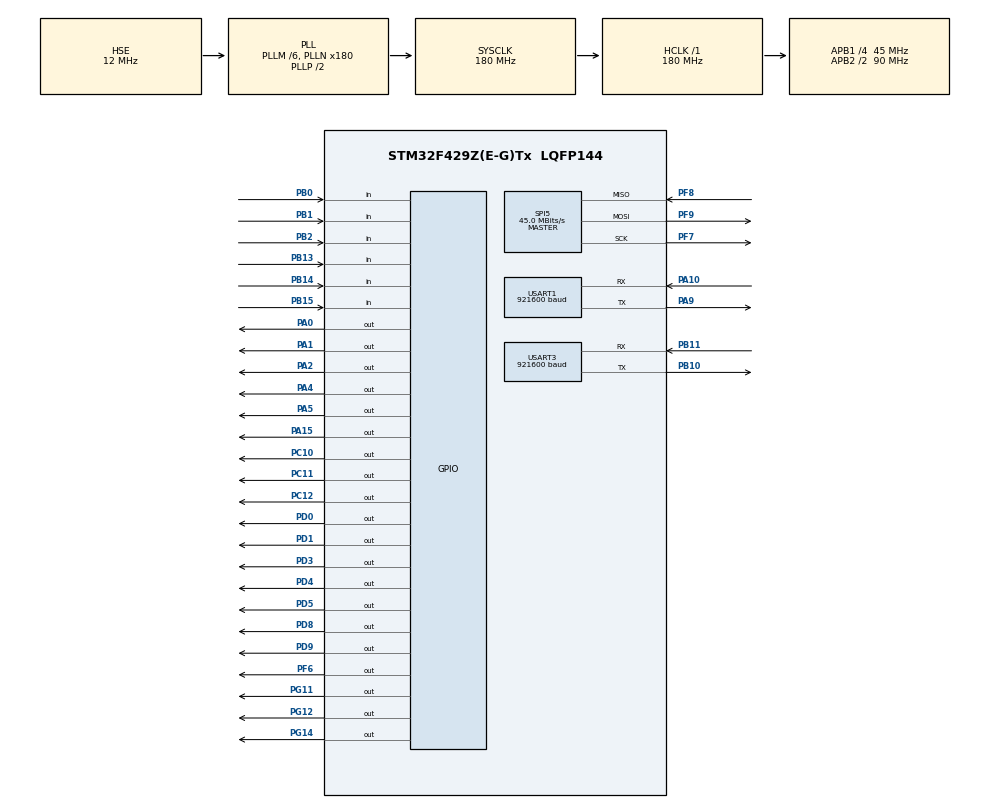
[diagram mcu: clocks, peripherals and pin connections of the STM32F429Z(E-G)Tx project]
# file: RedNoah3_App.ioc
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Dma.Request0=USART1_TX
Dma.Request1=USART1_RX
Dma.USART1_RX.1.Direction=DMA_PERIPH_TO_MEMORY
Dma.USART1_RX.1.FIFOMode=DMA_FIFOMODE_DISABLE
Dma.USART1_RX.1.Instance=DMA2_Stream2
Dma.USART1_RX.1.MemDataAlignment=DMA_MDATAALIGN_BYTE
Dma.USART1_RX.1.MemInc=DMA_MINC_ENABLE
Dma.USART1_RX.1.Mode=DMA_NORMAL
Dma.USART1_RX.1.PeriphDataAlignment=DMA_PDATAALIGN_BYTE
Dma.USART1_RX.1.PeriphInc=DMA_PINC_DISABLE
Dma.USART1_RX.1.Priority=DMA_PRIORITY_HIGH
Dma.USART1_TX.0.Direction=DMA_MEMORY_TO_PERIPH
Dma.USART1_TX.0.FIFOMode=DMA_FIFOMODE_DISABLE
Dma.USART1_TX.0.Instance=DMA2_Stream7
Dma.USART1_TX.0.MemDataAlignment=DMA_MDATAALIGN_BYTE
Dma.USART1_TX.0.MemInc=DMA_MINC_ENABLE
Dma.USART1_TX.0.Mode=DMA_NORMAL
Dma.USART1_TX.0.PeriphDataAlignment=DMA_PDATAALIGN_BYTE
Dma.USART1_TX.0.PeriphInc=DMA_PINC_DISABLE
Dma.USART1_TX.0.Priority=DMA_PRIORITY_HIGH
Mcu.Family=STM32F4
Mcu.Name=STM32F429Z(E-G)Tx
Mcu.Package=LQFP144
NVIC.DMA2_Stream2_IRQn=true\:0\:0\:false\:false\:true\:false\:true\:true
NVIC.DMA2_Stream7_IRQn=true\:0\:0\:false\:false\:true\:false\:true\:true
NVIC.PriorityGroup=NVIC_PRIORITYGROUP_4
NVIC.SPI5_IRQn=true\:0\:0\:false\:false\:true\:true\:true\:true
NVIC.TIM1_UP_TIM10_IRQn=true\:0\:0\:false\:false\:true\:true\:true\:true
NVIC.TIM7_IRQn=true\:10\:0\:true\:false\:true\:true\:true\:true
NVIC.USART1_IRQn=true\:0\:0\:false\:false\:true\:true\:true\:true
NVIC.USART3_IRQn=true\:0\:0\:false\:false\:true\:true\:true\:true
PA0/WKUP.Signal=GPIO_Output
PA1.Signal=GPIO_Output
PA10.Mode=Asynchronous
PA10.Signal=USART1_RX
PA13.Mode=Serial_Wire
PA13.Signal=SYS_JTMS-SWDIO
PA14.Mode=Serial_Wire
PA14.Signal=SYS_JTCK-SWCLK
PA15.Signal=GPIO_Output
PA2.Signal=GPIO_Output
PA4.Signal=GPIO_Output
PA5.Signal=GPIO_Output
PA9.Mode=Asynchronous
PA9.Signal=USART1_TX
PB0.Signal=GPIO_Input
PB1.Signal=GPIO_Input
PB10.Mode=Asynchronous
PB10.Signal=USART3_TX
PB11.Mode=Asynchronous
PB11.Signal=USART3_RX
PB13.Signal=GPIO_Input
PB14.Signal=GPIO_Input
PB15.Signal=GPIO_Input
PB2/BOOT1.Signal=GPIO_Input
PC10.Signal=GPIO_Output
PC11.Signal=GPIO_Output
PC12.Signal=GPIO_Output
PD0.Signal=GPIO_Output
PD1.Signal=GPIO_Output
PD3.Signal=GPIO_Output
PD4.Signal=GPIO_Output
PD5.Signal=GPIO_Output
PD8.Signal=GPIO_Output
PD9.Signal=GPIO_Output
PF6.Signal=GPIO_Output
PF7.Mode=Full_Duplex_Master
PF7.Signal=SPI5_SCK
PF8.Mode=Full_Duplex_Master
PF8.Signal=SPI5_MISO
PF9.Mode=Full_Duplex_Master
PF9.Signal=SPI5_MOSI
PG11.Signal=GPIO_Output
PG12.Signal=GPIO_Output
PG14.Signal=GPIO_Output
PH0/OSC_IN.Mode=HSE-External-Oscillator
PH0/OSC_IN.Signal=RCC_OSC_IN
PH1/OSC_OUT.Mode=HSE-External-Oscillator
PH1/OSC_OUT.Signal=RCC_OSC_OUT
ProjectManager.HeapSize=0x200
ProjectManager.StackSize=0x400
ProjectManager.TargetToolchain=MDK-ARM V5.32
RCC.48MHZClocksFreq_Value=90000000
RCC.AHBFreq_Value=180000000
RCC.APB1CLKDivider=RCC_HCLK_DIV4
RCC.APB1Freq_Value=45000000
RCC.APB1TimFreq_Value=90000000
RCC.APB2CLKDivider=RCC_HCLK_DIV2
RCC.APB2Freq_Value=90000000
RCC.APB2TimFreq_Value=180000000
RCC.CortexFreq_Value=180000000
RCC.HCLKFreq_Value=180000000
RCC.HSE_VALUE=12000000
RCC.HSI_VALUE=16000000
RCC.LSE_VALUE=32768
RCC.PLLM=6
RCC.PLLN=180
RCC.PLLSourceVirtual=RCC_PLLSOURCE_HSE
RCC.SYSCLKFreq_VALUE=180000000
RCC.SYSCLKSource=RCC_SYSCLKSOURCE_PLLCLK
RCC.VCOOutputFreq_Value=360000000
SPI5.BaudRatePrescaler=SPI_BAUDRATEPRESCALER_2
SPI5.CalculateBaudRate=45.0 MBits/s
SPI5.Direction=SPI_DIRECTION_2LINES
SPI5.Mode=SPI_MODE_MASTER
SPI5.VirtualType=VM_MASTER
USART1.BaudRate=921600
USART1.VirtualMode=VM_ASYNC
USART3.BaudRate=921600
USART3.VirtualMode=VM_ASYNC
VP_TIM10_VS_ClockSourceINT.Mode=Enable_Timer
VP_TIM7_VS_ClockSourceINT.Mode=Enable_Timer
board=custom

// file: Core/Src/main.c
/* USER CODE BEGIN Header */
/**
 ******************************************************************************
 * @file           : main.c
 * @brief          : Main program body
 ******************************************************************************
 * @attention
 *
 * Copyright (c) 2023 STMicroelectronics.
 * All rights reserved.
 *
 * This software is licensed under terms that can be found in the LICENSE file
 * in the root directory of this software component.
 * If no LICENSE file comes with this software, it is provided AS-IS.
 *
 ******************************************************************************
 */
/* USER CODE END Header */
#include "main.h"

SPI_HandleTypeDef hspi5;

TIM_HandleTypeDef htim7;
TIM_HandleTypeDef htim10;

UART_HandleTypeDef huart1;
UART_HandleTypeDef huart3;
DMA_HandleTypeDef hdma_usart1_tx;
DMA_HandleTypeDef hdma_usart1_rx;

void SystemClock_Config(void);
static void MX_GPIO_Init(void);
static void MX_DMA_Init(void);
static void MX_SPI5_Init(void);
static void MX_TIM7_Init(void);
static void MX_TIM10_Init(void);
static void MX_USART1_UART_Init(void);
static void MX_USART3_UART_Init(void);

int main(void)
{

  /* MCU Configuration--------------------------------------------------------*/

  /* Reset of all peripherals, Initializes the Flash interface and the Systick. */
  HAL_Init();

  /* Configure the system clock */
  SystemClock_Config();

  /* Initialize all configured peripherals */
  MX_GPIO_Init();
  MX_DMA_Init();
  MX_SPI5_Init();
  MX_TIM7_Init();
  MX_TIM10_Init();
  MX_USART1_UART_Init();
  MX_USART3_UART_Init();
  /* USER CODE BEGIN 2 */
  init_redhoah3_system();

  /* USER CODE END 2 */

  /* Infinite loop */
  /* USER CODE BEGIN WHILE */
  while (1)
  {
    rednoah3_main_task();
    /* USER CODE END WHILE */

  }
}

void SystemClock_Config(void)
{
  RCC_OscInitTypeDef RCC_OscInitStruct = {0};
  RCC_ClkInitTypeDef RCC_ClkInitStruct = {0};

  /** Configure the main internal regulator output voltage
  */
  __HAL_RCC_PWR_CLK_ENABLE();
  __HAL_PWR_VOLTAGESCALING_CONFIG(PWR_REGULATOR_VOLTAGE_SCALE1);

  /** Initializes the RCC Oscillators according to the specified parameters
  * in the RCC_OscInitTypeDef structure.
  */
  RCC_OscInitStruct.OscillatorType = RCC_OSCILLATORTYPE_HSE;
  RCC_OscInitStruct.HSEState = RCC_HSE_ON;
  RCC_OscInitStruct.PLL.PLLState = RCC_PLL_ON;
  RCC_OscInitStruct.PLL.PLLSource = RCC_PLLSOURCE_HSE;
  RCC_OscInitStruct.PLL.PLLM = 6;
  RCC_OscInitStruct.PLL.PLLN = 180;
  RCC_OscInitStruct.PLL.PLLP = RCC_PLLP_DIV2;
  RCC_OscInitStruct.PLL.PLLQ = 4;
  if (HAL_RCC_OscConfig(&RCC_OscInitStruct) != HAL_OK)
  {
    Error_Handler();
  }

  /** Activate the Over-Drive mode
  */
  if (HAL_PWREx_EnableOverDrive() != HAL_OK)
  {
    Error_Handler();
  }

  /** Initializes the CPU, AHB and APB buses clocks
  */
  RCC_ClkInitStruct.ClockType = RCC_CLOCKTYPE_HCLK|RCC_CLOCKTYPE_SYSCLK
                              |RCC_CLOCKTYPE_PCLK1|RCC_CLOCKTYPE_PCLK2;
  RCC_ClkInitStruct.SYSCLKSource = RCC_SYSCLKSOURCE_PLLCLK;
  RCC_ClkInitStruct.AHBCLKDivider = RCC_SYSCLK_DIV1;
  RCC_ClkInitStruct.APB1CLKDivider = RCC_HCLK_DIV4;
  RCC_ClkInitStruct.APB2CLKDivider = RCC_HCLK_DIV2;

  if (HAL_RCC_ClockConfig(&RCC_ClkInitStruct, FLASH_LATENCY_5) != HAL_OK)
  {
    Error_Handler();
  }
}

static void MX_SPI5_Init(void)
{

  /* SPI5 parameter configuration*/
  hspi5.Instance = SPI5;
  hspi5.Init.Mode = SPI_MODE_MASTER;
  hspi5.Init.Direction = SPI_DIRECTION_2LINES;
  hspi5.Init.DataSize = SPI_DATASIZE_8BIT;
  hspi5.Init.CLKPolarity = SPI_POLARITY_LOW;
  hspi5.Init.CLKPhase = SPI_PHASE_1EDGE;
  hspi5.Init.NSS = SPI_NSS_SOFT;
  hspi5.Init.BaudRatePrescaler = SPI_BAUDRATEPRESCALER_2;
  hspi5.Init.FirstBit = SPI_FIRSTBIT_MSB;
  hspi5.Init.TIMode = SPI_TIMODE_DISABLE;
  hspi5.Init.CRCCalculation = SPI_CRCCALCULATION_DISABLE;
  hspi5.Init.CRCPolynomial = 10;
  if (HAL_SPI_Init(&hspi5) != HAL_OK)
  {
    Error_Handler();
  }
  /* USER CODE BEGIN SPI5_Init 2 */
	hspi5.Init.BaudRatePrescaler = SPI_BAUDRATEPRESCALER_128;
	hspi5.Init.CLKPolarity = SPI_POLARITY_LOW;
  hspi5.Init.CLKPhase = SPI_PHASE_2EDGE;
	HAL_GPIO_WritePin(GPIOF, GPIO_PIN_6, 1);

	 if (HAL_SPI_Init(&hspi5) != HAL_OK)
  {
    Error_Handler();
  }

  /* USER CODE END SPI5_Init 2 */

}

static void MX_TIM7_Init(void)
{

  TIM_MasterConfigTypeDef sMasterConfig = {0};

  htim7.Instance = TIM7;
  htim7.Init.Prescaler = 0;
  htim7.Init.CounterMode = TIM_COUNTERMODE_UP;
  htim7.Init.Period = 65535;
  htim7.Init.AutoReloadPreload = TIM_AUTORELOAD_PRELOAD_DISABLE;
  if (HAL_TIM_Base_Init(&htim7) != HAL_OK)
  {
    Error_Handler();
  }
  sMasterConfig.MasterOutputTrigger = TIM_TRGO_RESET;
  sMasterConfig.MasterSlaveMode = TIM_MASTERSLAVEMODE_DISABLE;
  if (HAL_TIMEx_MasterConfigSynchronization(&htim7, &sMasterConfig) != HAL_OK)
  {
    Error_Handler();
  }

}

static void MX_TIM10_Init(void)
{

  htim10.Instance = TIM10;
  htim10.Init.Prescaler = 0;
  htim10.Init.CounterMode = TIM_COUNTERMODE_UP;
  htim10.Init.Period = 65535;
  htim10.Init.ClockDivision = TIM_CLOCKDIVISION_DIV1;
  htim10.Init.AutoReloadPreload = TIM_AUTORELOAD_PRELOAD_DISABLE;
  if (HAL_TIM_Base_Init(&htim10) != HAL_OK)
  {
    Error_Handler();
  }

}

static void MX_USART1_UART_Init(void)
{

  huart1.Instance = USART1;
  huart1.Init.BaudRate = 921600;
  huart1.Init.WordLength = UART_WORDLENGTH_8B;
  huart1.Init.StopBits = UART_STOPBITS_1;
  huart1.Init.Parity = UART_PARITY_NONE;
  huart1.Init.Mode = UART_MODE_TX_RX;
  huart1.Init.HwFlowCtl = UART_HWCONTROL_NONE;
  huart1.Init.OverSampling = UART_OVERSAMPLING_16;
  if (HAL_UART_Init(&huart1) != HAL_OK)
  {
    Error_Handler();
  }

}

static void MX_USART3_UART_Init(void)
{

  huart3.Instance = USART3;
  huart3.Init.BaudRate = 921600;
  huart3.Init.WordLength = UART_WORDLENGTH_8B;
  huart3.Init.StopBits = UART_STOPBITS_1;
  huart3.Init.Parity = UART_PARITY_NONE;
  huart3.Init.Mode = UART_MODE_TX_RX;
  huart3.Init.HwFlowCtl = UART_HWCONTROL_NONE;
  huart3.Init.OverSampling = UART_OVERSAMPLING_16;
  if (HAL_UART_Init(&huart3) != HAL_OK)
  {
    Error_Handler();
  }

}

static void MX_DMA_Init(void)
{

  /* DMA controller clock enable */
  __HAL_RCC_DMA2_CLK_ENABLE();

  /* DMA interrupt init */
  /* DMA2_Stream2_IRQn interrupt configuration */
  HAL_NVIC_SetPriority(DMA2_Stream2_IRQn, 0, 0);
  HAL_NVIC_EnableIRQ(DMA2_Stream2_IRQn);
  /* DMA2_Stream7_IRQn interrupt configuration */
  HAL_NVIC_SetPriority(DMA2_Stream7_IRQn, 0, 0);
  HAL_NVIC_EnableIRQ(DMA2_Stream7_IRQn);

}

static void MX_GPIO_Init(void)
{
  GPIO_InitTypeDef GPIO_InitStruct = {0};

  /* GPIO Ports Clock Enable */
  __HAL_RCC_GPIOE_CLK_ENABLE();
  __HAL_RCC_GPIOF_CLK_ENABLE();
  __HAL_RCC_GPIOH_CLK_ENABLE();
  __HAL_RCC_GPIOA_CLK_ENABLE();
  __HAL_RCC_GPIOB_CLK_ENABLE();
  __HAL_RCC_GPIOD_CLK_ENABLE();
  __HAL_RCC_GPIOC_CLK_ENABLE();
  __HAL_RCC_GPIOG_CLK_ENABLE();

  /*Configure GPIO pin Output Level */
  HAL_GPIO_WritePin(GPIOE, GPIO_PIN_3|GPIO_PIN_4, GPIO_PIN_RESET);

  /*Configure GPIO pin Output Level */
  HAL_GPIO_WritePin(GPIOF, GPIO_PIN_6, GPIO_PIN_RESET);

  /*Configure GPIO pin Output Level */
  HAL_GPIO_WritePin(GPIOA, GPIO_PIN_0|GPIO_PIN_1|GPIO_PIN_2|GPIO_PIN_4
                          |GPIO_PIN_5|GPIO_PIN_15, GPIO_PIN_RESET);

  /*Configure GPIO pin Output Level */
  HAL_GPIO_WritePin(GPIOD, GPIO_PIN_8|GPIO_PIN_9|GPIO_PIN_0|GPIO_PIN_1
                          |GPIO_PIN_3|GPIO_PIN_4|GPIO_PIN_5, GPIO_PIN_RESET);

  /*Configure GPIO pin Output Level */
  HAL_GPIO_WritePin(GPIOC, GPIO_PIN_10|GPIO_PIN_11|GPIO_PIN_12, GPIO_PIN_RESET);

  /*Configure GPIO pin Output Level */
  HAL_GPIO_WritePin(GPIOG, GPIO_PIN_11|GPIO_PIN_12|GPIO_PIN_14, GPIO_PIN_RESET);

  /*Configure GPIO pins : PE3 PE4 */
  GPIO_InitStruct.Pin = GPIO_PIN_3|GPIO_PIN_4;
  GPIO_InitStruct.Mode = GPIO_MODE_OUTPUT_PP;
  GPIO_InitStruct.Pull = GPIO_NOPULL;
  GPIO_InitStruct.Speed = GPIO_SPEED_FREQ_LOW;
  HAL_GPIO_Init(GPIOE, &GPIO_InitStruct);

  /*Configure GPIO pin : PF6 */
  GPIO_InitStruct.Pin = GPIO_PIN_6;
  GPIO_InitStruct.Mode = GPIO_MODE_OUTPUT_PP;
  GPIO_InitStruct.Pull = GPIO_NOPULL;
  GPIO_InitStruct.Speed = GPIO_SPEED_FREQ_LOW;
  HAL_GPIO_Init(GPIOF, &GPIO_InitStruct);

  /*Configure GPIO pins : PA0 PA1 PA2 PA4
                           PA5 PA15 */
  GPIO_InitStruct.Pin = GPIO_PIN_0|GPIO_PIN_1|GPIO_PIN_2|GPIO_PIN_4
                          |GPIO_PIN_5|GPIO_PIN_15;
  GPIO_InitStruct.Mode = GPIO_MODE_OUTPUT_PP;
  GPIO_InitStruct.Pull = GPIO_NOPULL;
  GPIO_InitStruct.Speed = GPIO_SPEED_FREQ_LOW;
  HAL_GPIO_Init(GPIOA, &GPIO_InitStruct);

  /*Configure GPIO pins : PB0 PB1 PB2 PB13
                           PB14 PB15 */
  GPIO_InitStruct.Pin = GPIO_PIN_0|GPIO_PIN_1|GPIO_PIN_2|GPIO_PIN_13
                          |GPIO_PIN_14|GPIO_PIN_15;
  GPIO_InitStruct.Mode = GPIO_MODE_INPUT;
  GPIO_InitStruct.Pull = GPIO_NOPULL;
  HAL_GPIO_Init(GPIOB, &GPIO_InitStruct);

  /*Configure GPIO pins : PD8 PD9 PD0 PD1
                           PD3 PD4 PD5 */
  GPIO_InitStruct.Pin = GPIO_PIN_8|GPIO_PIN_9|GPIO_PIN_0|GPIO_PIN_1
                          |GPIO_PIN_3|GPIO_PIN_4|GPIO_PIN_5;
  GPIO_InitStruct.Mode = GPIO_MODE_OUTPUT_PP;
  GPIO_InitStruct.Pull = GPIO_NOPULL;
  GPIO_InitStruct.Speed = GPIO_SPEED_FREQ_LOW;
  HAL_GPIO_Init(GPIOD, &GPIO_InitStruct);

  /*Configure GPIO pins : PC10 PC11 PC12 */
  GPIO_InitStruct.Pin = GPIO_PIN_10|GPIO_PIN_11|GPIO_PIN_12;
  GPIO_InitStruct.Mode = GPIO_MODE_OUTPUT_PP;
  GPIO_InitStruct.Pull = GPIO_NOPULL;
  GPIO_InitStruct.Speed = GPIO_SPEED_FREQ_LOW;
  HAL_GPIO_Init(GPIOC, &GPIO_InitStruct);

  /*Configure GPIO pins : PG11 PG12 PG14 */
  GPIO_InitStruct.Pin = GPIO_PIN_11|GPIO_PIN_12|GPIO_PIN_14;
  GPIO_InitStruct.Mode = GPIO_MODE_OUTPUT_PP;
  GPIO_InitStruct.Pull = GPIO_NOPULL;
  GPIO_InitStruct.Speed = GPIO_SPEED_FREQ_LOW;
  HAL_GPIO_Init(GPIOG, &GPIO_InitStruct);

}

void Error_Handler(void)
{
  __disable_irq();
  while (1)
  {
  }
}
